VERSION 5.7 ;
BUSBITCHARS "[]" ;
DIVIDERCHAR "/" ;
UNITS
  DATABASE MICRONS 1000 ;
END UNITS

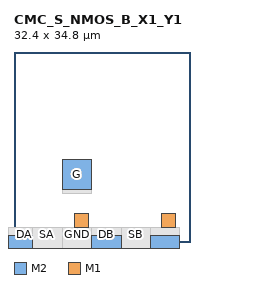
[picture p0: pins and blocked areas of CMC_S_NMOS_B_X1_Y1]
MACRO CMC_S_NMOS_B_X1_Y1
  CLASS BLOCK ;
  ORIGIN 1.000 1.000 ;
  FOREIGN CMC_S_NMOS_B_X1_Y1 1.000 1.000 ;
  SIZE 32.400 BY 34.800 ;
  PIN DA
    DIRECTION INOUT ;
    USE SIGNAL ;
    PORT
      LAYER M2 ;
        RECT -3.000 -5.300 2.400 0.100 ;
    END
  END DA
  PIN DB
    DIRECTION INOUT ;
    USE SIGNAL ;
    PORT
      LAYER M2 ;
        RECT 13.200 -5.300 18.600 0.100 ;
    END
  END DB
  PIN G
    DIRECTION INPUT ;
    USE SIGNAL ;
    PORT
      LAYER M2 ;
        RECT 7.800 8.700 13.200 14.100 ;
    END
  END G
  PIN SA
    DIRECTION INOUT ;
    USE SIGNAL ;
    PORT
      LAYER M2 ;
        RECT 2.400 -12.900 7.800 -7.500 ;
    END
  END SA
  PIN SB
    DIRECTION INOUT ;
    USE SIGNAL ;
    PORT
      LAYER M2 ;
        RECT 18.600 -12.900 24.000 -7.500 ;
    END
  END SB
  PIN GND
    DIRECTION INOUT ;
    USE SIGNAL ;
    PORT
      LAYER M1 ;
        RECT 10.000 1.600 12.600 4.200 ;
      LAYER M1 ;
        RECT 26.000 1.600 28.600 4.200 ;
      LAYER M2 ;
        RECT 7.800 -20.700 13.200 -15.300 ;
      LAYER M2 ;
        RECT 24.000 -5.300 29.400 0.100 ;
    END
  END GND
  OBS
    LAYER M1 ;
      RECT -3.000 -5.300 2.400 1.600 ;
    LAYER M1 ;
      RECT 2.400 -12.900 7.800 1.600 ;
    LAYER M1 ;
      RECT 7.800 -20.700 13.200 1.600 ;
    LAYER M1 ;
      RECT 13.200 -5.300 18.600 1.600 ;
    LAYER M1 ;
      RECT 18.600 -12.900 24.000 1.600 ;
    LAYER M1 ;
      RECT 24.000 -5.300 29.400 1.600 ;
    LAYER M1 ;
      RECT 7.800 7.800 13.200 14.100 ;
    LAYER V1 ;
      RECT 9.800 -18.700 11.200 -17.300 ;
    LAYER V1 ;
      RECT 4.400 -10.900 5.800 -9.500 ;
    LAYER V1 ;
      RECT 20.600 -10.900 22.000 -9.500 ;
    LAYER V1 ;
      RECT -1.000 -3.300 0.400 -1.900 ;
    LAYER V1 ;
      RECT 15.200 -3.300 16.600 -1.900 ;
    LAYER V1 ;
      RECT 26.000 -3.300 27.400 -1.900 ;
    LAYER V1 ;
      RECT 9.800 10.700 11.200 12.100 ;
  END
END CMC_S_NMOS_B_X1_Y1

END LIBRARY
